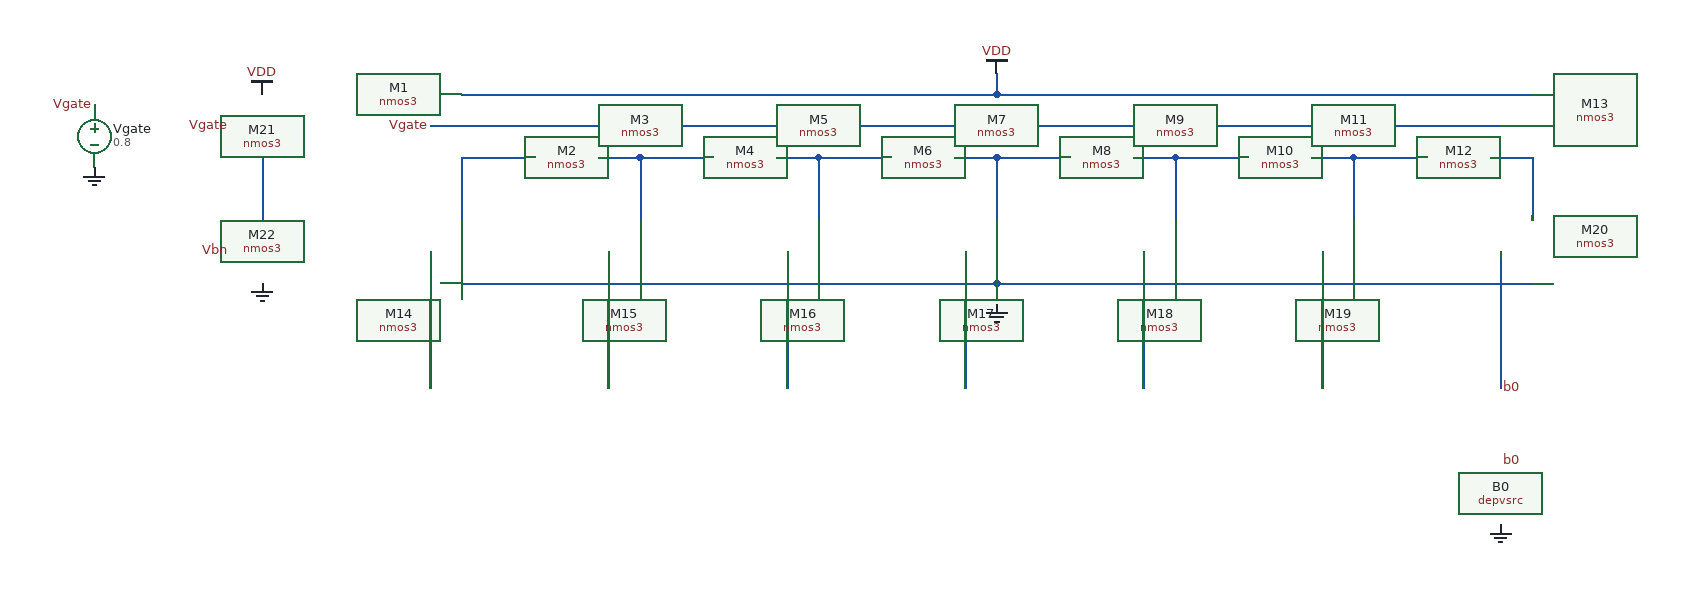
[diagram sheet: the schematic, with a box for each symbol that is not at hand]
v {xschem version=3.4.3 file_version=1.2
}
G {}
K {}
V {}
S {}
E {}
N 110 -290 180 -290 {
lab=#net1}
N 80 -320 210 -320 {
lab=Vgate}
N 210 -320 250 -320 {
lab=Vgate}
N 240 -290 280 -290 {
lab=#net2}
N 280 -290 350 -290 {
lab=#net2}
N 250 -320 380 -320 {
lab=Vgate}
N 380 -320 420 -320 {
lab=Vgate}
N 410 -290 450 -290 {
lab=#net3}
N 450 -290 520 -290 {
lab=#net3}
N 420 -320 550 -320 {
lab=Vgate}
N 550 -320 590 -320 {
lab=Vgate}
N 580 -290 620 -290 {
lab=#net4}
N 620 -290 690 -290 {
lab=#net4}
N 590 -320 720 -320 {
lab=Vgate}
N 720 -320 760 -320 {
lab=Vgate}
N 750 -290 790 -290 {
lab=#net5}
N 790 -290 860 -290 {
lab=#net5}
N 760 -320 890 -320 {
lab=Vgate}
N 890 -320 930 -320 {
lab=Vgate}
N 920 -290 960 -290 {
lab=#net6}
N 960 -290 1030 -290 {
lab=#net6}
N 930 -320 1060 -320 {
lab=Vgate}
N 1060 -320 1100 -320 {
lab=Vgate}
N 1090 -290 1130 -290 {
lab=#net7}
N 110 -290 110 -230 {
lab=#net1}
N 280 -290 280 -230 {
lab=#net2}
N 450 -290 450 -230 {
lab=#net3}
N 620 -290 620 -230 {
lab=#net4}
N 790 -290 790 -230 {
lab=#net5}
N 960 -290 960 -230 {
lab=#net6}
N 1130 -290 1130 -230 {
lab=#net7}
N 110 -170 280 -170 {
lab=GND}
N 280 -170 450 -170 {
lab=GND}
N 450 -170 620 -170 {
lab=GND}
N 620 -170 790 -170 {
lab=GND}
N 790 -170 960 -170 {
lab=GND}
N 960 -170 1130 -170 {
lab=GND}
N 620 -170 620 -150 {
lab=GND}
N 110 -350 280 -350 {
lab=VDD}
N 280 -350 450 -350 {
lab=VDD}
N 450 -350 620 -350 {
lab=VDD}
N 620 -350 790 -350 {
lab=VDD}
N 790 -350 960 -350 {
lab=VDD}
N 960 -350 1130 -350 {
lab=VDD}
N 620 -370 620 -350 {
lab=VDD}
N 80 -200 80 -70 {
lab=#net8}
N 250 -200 250 -70 {
lab=#net9}
N 420 -200 420 -70 {
lab=#net10}
N 590 -200 590 -70 {
lab=#net11}
N 760 -200 760 -70 {
lab=#net12}
N 930 -200 930 -70 {
lab=#net13}
N 1100 -200 1100 -70 {
lab=b0}
N -80 -290 -80 -230 {
lab=#net14}
C {madvlsi/nmos3.sym} 110 -320 0 0 {name=M1
L=\{L\}
W=\{W\}
body=GND
nf=1
mult=2
ad="'int((nf+1)/2) * W/nf * 0.29'" 
pd="'2*int((nf+1)/2) * (W/nf + 0.29)'"
as="'int((nf+2)/2) * W/nf * 0.29'" 
ps="'2*int((nf+2)/2) * (W/nf + 0.29)'"
nrd="'0.29 / W'" nrs="'0.29 / W'"
sa=0 sb=0 sd=0
model=nfet_01v8
spiceprefix=X
}
C {madvlsi/nmos3.sym} 210 -290 1 0 {name=M2
L=\{L\}
W=\{W\}
body=GND
nf=1
mult=2
ad="'int((nf+1)/2) * W/nf * 0.29'" 
pd="'2*int((nf+1)/2) * (W/nf + 0.29)'"
as="'int((nf+2)/2) * W/nf * 0.29'" 
ps="'2*int((nf+2)/2) * (W/nf + 0.29)'"
nrd="'0.29 / W'" nrs="'0.29 / W'"
sa=0 sb=0 sd=0
model=nfet_01v8
spiceprefix=X
}
C {madvlsi/nmos3.sym} 280 -320 0 0 {name=M3
L=\{L\}
W=\{W\}
body=GND
nf=1
mult=1
ad="'int((nf+1)/2) * W/nf * 0.29'" 
pd="'2*int((nf+1)/2) * (W/nf + 0.29)'"
as="'int((nf+2)/2) * W/nf * 0.29'" 
ps="'2*int((nf+2)/2) * (W/nf + 0.29)'"
nrd="'0.29 / W'" nrs="'0.29 / W'"
sa=0 sb=0 sd=0
model=nfet_01v8
spiceprefix=X
}
C {madvlsi/nmos3.sym} 380 -290 1 0 {name=M4
L=\{L\}
W=\{W\}
body=GND
nf=1
mult=2
ad="'int((nf+1)/2) * W/nf * 0.29'" 
pd="'2*int((nf+1)/2) * (W/nf + 0.29)'"
as="'int((nf+2)/2) * W/nf * 0.29'" 
ps="'2*int((nf+2)/2) * (W/nf + 0.29)'"
nrd="'0.29 / W'" nrs="'0.29 / W'"
sa=0 sb=0 sd=0
model=nfet_01v8
spiceprefix=X
}
C {madvlsi/nmos3.sym} 450 -320 0 0 {name=M5
L=\{L\}
W=\{W\}
body=GND
nf=1
mult=1
ad="'int((nf+1)/2) * W/nf * 0.29'" 
pd="'2*int((nf+1)/2) * (W/nf + 0.29)'"
as="'int((nf+2)/2) * W/nf * 0.29'" 
ps="'2*int((nf+2)/2) * (W/nf + 0.29)'"
nrd="'0.29 / W'" nrs="'0.29 / W'"
sa=0 sb=0 sd=0
model=nfet_01v8
spiceprefix=X
}
C {madvlsi/nmos3.sym} 550 -290 1 0 {name=M6
L=\{L\}
W=\{W\}
body=GND
nf=1
mult=2
ad="'int((nf+1)/2) * W/nf * 0.29'" 
pd="'2*int((nf+1)/2) * (W/nf + 0.29)'"
as="'int((nf+2)/2) * W/nf * 0.29'" 
ps="'2*int((nf+2)/2) * (W/nf + 0.29)'"
nrd="'0.29 / W'" nrs="'0.29 / W'"
sa=0 sb=0 sd=0
model=nfet_01v8
spiceprefix=X
}
C {madvlsi/nmos3.sym} 620 -320 0 0 {name=M7
L=\{L\}
W=\{W\}
body=GND
nf=1
mult=1
ad="'int((nf+1)/2) * W/nf * 0.29'" 
pd="'2*int((nf+1)/2) * (W/nf + 0.29)'"
as="'int((nf+2)/2) * W/nf * 0.29'" 
ps="'2*int((nf+2)/2) * (W/nf + 0.29)'"
nrd="'0.29 / W'" nrs="'0.29 / W'"
sa=0 sb=0 sd=0
model=nfet_01v8
spiceprefix=X
}
C {madvlsi/nmos3.sym} 720 -290 1 0 {name=M8
L=\{L\}
W=\{W\}
body=GND
nf=1
mult=2
ad="'int((nf+1)/2) * W/nf * 0.29'" 
pd="'2*int((nf+1)/2) * (W/nf + 0.29)'"
as="'int((nf+2)/2) * W/nf * 0.29'" 
ps="'2*int((nf+2)/2) * (W/nf + 0.29)'"
nrd="'0.29 / W'" nrs="'0.29 / W'"
sa=0 sb=0 sd=0
model=nfet_01v8
spiceprefix=X
}
C {madvlsi/nmos3.sym} 790 -320 0 0 {name=M9
L=\{L\}
W=\{W\}
body=GND
nf=1
mult=1
ad="'int((nf+1)/2) * W/nf * 0.29'" 
pd="'2*int((nf+1)/2) * (W/nf + 0.29)'"
as="'int((nf+2)/2) * W/nf * 0.29'" 
ps="'2*int((nf+2)/2) * (W/nf + 0.29)'"
nrd="'0.29 / W'" nrs="'0.29 / W'"
sa=0 sb=0 sd=0
model=nfet_01v8
spiceprefix=X
}
C {madvlsi/nmos3.sym} 890 -290 1 0 {name=M10
L=\{L\}
W=\{W\}
body=GND
nf=1
mult=2
ad="'int((nf+1)/2) * W/nf * 0.29'" 
pd="'2*int((nf+1)/2) * (W/nf + 0.29)'"
as="'int((nf+2)/2) * W/nf * 0.29'" 
ps="'2*int((nf+2)/2) * (W/nf + 0.29)'"
nrd="'0.29 / W'" nrs="'0.29 / W'"
sa=0 sb=0 sd=0
model=nfet_01v8
spiceprefix=X
}
C {madvlsi/nmos3.sym} 960 -320 0 0 {name=M11
L=\{L\}
W=\{W\}
body=GND
nf=1
mult=1
ad="'int((nf+1)/2) * W/nf * 0.29'" 
pd="'2*int((nf+1)/2) * (W/nf + 0.29)'"
as="'int((nf+2)/2) * W/nf * 0.29'" 
ps="'2*int((nf+2)/2) * (W/nf + 0.29)'"
nrd="'0.29 / W'" nrs="'0.29 / W'"
sa=0 sb=0 sd=0
model=nfet_01v8
spiceprefix=X
}
C {madvlsi/nmos3.sym} 1060 -290 1 0 {name=M12
L=\{L\}
W=\{W\}
body=GND
nf=1
mult=2
ad="'int((nf+1)/2) * W/nf * 0.29'" 
pd="'2*int((nf+1)/2) * (W/nf + 0.29)'"
as="'int((nf+2)/2) * W/nf * 0.29'" 
ps="'2*int((nf+2)/2) * (W/nf + 0.29)'"
nrd="'0.29 / W'" nrs="'0.29 / W'"
sa=0 sb=0 sd=0
model=nfet_01v8
spiceprefix=X
}
C {madvlsi/nmos3.sym} 1130 -320 0 0 {name=M13
L=\{L\}
W=\{W\}
body=GND
nf=1
mult=2
ad="'int((nf+1)/2) * W/nf * 0.29'" 
pd="'2*int((nf+1)/2) * (W/nf + 0.29)'"
as="'int((nf+2)/2) * W/nf * 0.29'" 
ps="'2*int((nf+2)/2) * (W/nf + 0.29)'"
nrd="'0.29 / W'" nrs="'0.29 / W'"
sa=0 sb=0 sd=0
model=nfet_01v8
spiceprefix=X
}
C {madvlsi/nmos3.sym} 110 -200 0 0 {name=M14
L=\{L\}
W=\{W\}
body=GND
nf=1
mult=1
ad="'int((nf+1)/2) * W/nf * 0.29'" 
pd="'2*int((nf+1)/2) * (W/nf + 0.29)'"
as="'int((nf+2)/2) * W/nf * 0.29'" 
ps="'2*int((nf+2)/2) * (W/nf + 0.29)'"
nrd="'0.29 / W'" nrs="'0.29 / W'"
sa=0 sb=0 sd=0
model=nfet_01v8
spiceprefix=X
}
C {madvlsi/nmos3.sym} 280 -200 0 0 {name=M15
L=\{L\}
W=\{W\}
body=GND
nf=1
mult=1
ad="'int((nf+1)/2) * W/nf * 0.29'" 
pd="'2*int((nf+1)/2) * (W/nf + 0.29)'"
as="'int((nf+2)/2) * W/nf * 0.29'" 
ps="'2*int((nf+2)/2) * (W/nf + 0.29)'"
nrd="'0.29 / W'" nrs="'0.29 / W'"
sa=0 sb=0 sd=0
model=nfet_01v8
spiceprefix=X
}
C {madvlsi/nmos3.sym} 450 -200 0 0 {name=M16
L=\{L\}
W=\{W\}
body=GND
nf=1
mult=1
ad="'int((nf+1)/2) * W/nf * 0.29'" 
pd="'2*int((nf+1)/2) * (W/nf + 0.29)'"
as="'int((nf+2)/2) * W/nf * 0.29'" 
ps="'2*int((nf+2)/2) * (W/nf + 0.29)'"
nrd="'0.29 / W'" nrs="'0.29 / W'"
sa=0 sb=0 sd=0
model=nfet_01v8
spiceprefix=X
}
C {madvlsi/nmos3.sym} 620 -200 0 0 {name=M17
L=\{L\}
W=\{W\}
body=GND
nf=1
mult=1
ad="'int((nf+1)/2) * W/nf * 0.29'" 
pd="'2*int((nf+1)/2) * (W/nf + 0.29)'"
as="'int((nf+2)/2) * W/nf * 0.29'" 
ps="'2*int((nf+2)/2) * (W/nf + 0.29)'"
nrd="'0.29 / W'" nrs="'0.29 / W'"
sa=0 sb=0 sd=0
model=nfet_01v8
spiceprefix=X
}
C {madvlsi/nmos3.sym} 790 -200 0 0 {name=M18
L=\{L\}
W=\{W\}
body=GND
nf=1
mult=1
ad="'int((nf+1)/2) * W/nf * 0.29'" 
pd="'2*int((nf+1)/2) * (W/nf + 0.29)'"
as="'int((nf+2)/2) * W/nf * 0.29'" 
ps="'2*int((nf+2)/2) * (W/nf + 0.29)'"
nrd="'0.29 / W'" nrs="'0.29 / W'"
sa=0 sb=0 sd=0
model=nfet_01v8
spiceprefix=X
}
C {madvlsi/nmos3.sym} 960 -200 0 0 {name=M19
L=\{L\}
W=\{W\}
body=GND
nf=1
mult=1
ad="'int((nf+1)/2) * W/nf * 0.29'" 
pd="'2*int((nf+1)/2) * (W/nf + 0.29)'"
as="'int((nf+2)/2) * W/nf * 0.29'" 
ps="'2*int((nf+2)/2) * (W/nf + 0.29)'"
nrd="'0.29 / W'" nrs="'0.29 / W'"
sa=0 sb=0 sd=0
model=nfet_01v8
spiceprefix=X
}
C {madvlsi/nmos3.sym} 1130 -200 0 0 {name=M20
L=\{L\}
W=\{W\}
body=GND
nf=1
mult=1
ad="'int((nf+1)/2) * W/nf * 0.29'" 
pd="'2*int((nf+1)/2) * (W/nf + 0.29)'"
as="'int((nf+2)/2) * W/nf * 0.29'" 
ps="'2*int((nf+2)/2) * (W/nf + 0.29)'"
nrd="'0.29 / W'" nrs="'0.29 / W'"
sa=0 sb=0 sd=0
model=nfet_01v8
spiceprefix=X
}
C {madvlsi/gnd.sym} 620 -150 0 0 {name=l1 lab=GND}
C {madvlsi/vdd.sym} 620 -370 0 0 {name=l2 lab=VDD}
C {madvlsi/vsource.sym} -240 -310 0 0 {name=Vgate
value=0.8}
C {madvlsi/gnd.sym} -240 -280 0 0 {name=l5 lab=GND}
C {devices/lab_pin.sym} -240 -340 1 0 {name=p1 sig_type=std_logic lab=Vgate
}
C {devices/lab_pin.sym} 80 -320 0 0 {name=p2 sig_type=std_logic lab=Vgate
}
C {devices/lab_pin.sym} 1100 -70 2 0 {name=p4 sig_type=std_logic lab=b0
}
C {madvlsi/nmos3.sym} -80 -320 0 0 {name=M21
L=\{L\}
W=\{W\}
body=GND
nf=1
mult=2
ad="'int((nf+1)/2) * W/nf * 0.29'" 
pd="'2*int((nf+1)/2) * (W/nf + 0.29)'"
as="'int((nf+2)/2) * W/nf * 0.29'" 
ps="'2*int((nf+2)/2) * (W/nf + 0.29)'"
nrd="'0.29 / W'" nrs="'0.29 / W'"
sa=0 sb=0 sd=0
model=nfet_01v8
spiceprefix=X
}
C {madvlsi/nmos3.sym} -80 -200 0 0 {name=M22
L=\{L\}
W=\{W\}
body=GND
nf=1
mult=1
ad="'int((nf+1)/2) * W/nf * 0.29'" 
pd="'2*int((nf+1)/2) * (W/nf + 0.29)'"
as="'int((nf+2)/2) * W/nf * 0.29'" 
ps="'2*int((nf+2)/2) * (W/nf + 0.29)'"
nrd="'0.29 / W'" nrs="'0.29 / W'"
sa=0 sb=0 sd=0
model=nfet_01v8
spiceprefix=X
}
C {madvlsi/vdd.sym} -80 -350 0 0 {name=l4 lab=VDD}
C {madvlsi/gnd.sym} -80 -170 0 0 {name=l6 lab=GND}
C {devices/lab_pin.sym} -110 -320 0 0 {name=p5 sig_type=std_logic lab=Vgate
}
C {devices/lab_pin.sym} -110 -200 0 0 {name=p3 sig_type=std_logic lab=Vbn
}
C {madvlsi/depvsrc.sym} 1100 30 0 0 {name=B0
func=Vbn}
C {devices/lab_pin.sym} 1100 0 2 0 {name=p6 sig_type=std_logic lab=b0
}
C {madvlsi/gnd.sym} 1100 60 0 0 {name=l3 lab=GND}
